One B-rep face of a CAD part: STEP entity #672.
In plain terms, the planar face has unit normal (0, -1, 0).
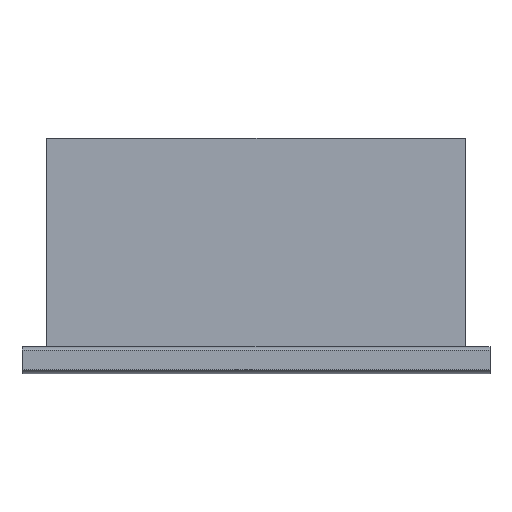
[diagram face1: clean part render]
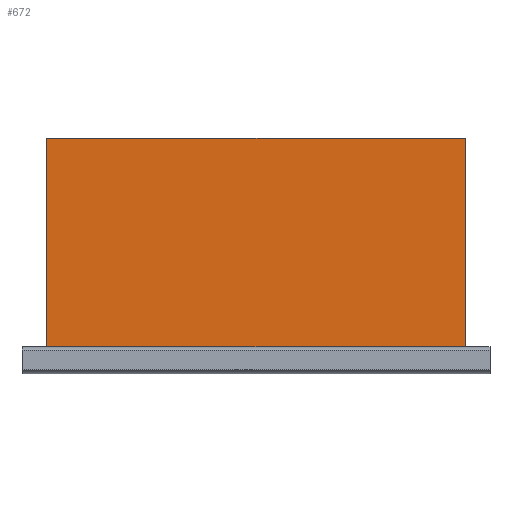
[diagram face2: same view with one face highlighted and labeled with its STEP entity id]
Its self-contained STEP definition (entity closure, numbers rounded to 3 decimals):
#117 = CYLINDRICAL_SURFACE('',#118,1.1);
#118 = AXIS2_PLACEMENT_3D('',#119,#120,#121);
#119 = CARTESIAN_POINT('',(-19.,0.,0.));
#120 = DIRECTION('',(1.,0.,0.));
#121 = DIRECTION('',(0.,0.,-1.));
#144 = PLANE('',#145);
#145 = AXIS2_PLACEMENT_3D('',#146,#147,#148);
#146 = CARTESIAN_POINT('',(-17.,-0.25,0.));
#147 = DIRECTION('',(1.,0.,0.));
#148 = DIRECTION('',(0.,0.,1.));
#172 = PLANE('',#173);
#173 = AXIS2_PLACEMENT_3D('',#174,#175,#176);
#174 = CARTESIAN_POINT('',(-17.,-0.25,18.));
#175 = DIRECTION('',(0.,0.,1.));
#176 = DIRECTION('',(1.,0.,-0.));
#200 = PLANE('',#201);
#201 = AXIS2_PLACEMENT_3D('',#202,#203,#204);
#202 = CARTESIAN_POINT('',(17.,-0.25,0.));
#203 = DIRECTION('',(1.,0.,0.));
#204 = DIRECTION('',(0.,0.,1.));
#397 = VERTEX_POINT('',#398);
#398 = CARTESIAN_POINT('',(17.,-0.25,1.071));
#420 = EDGE_CURVE('',#421,#397,#423,.T.);
#421 = VERTEX_POINT('',#422);
#422 = CARTESIAN_POINT('',(-17.,-0.25,1.071));
#423 = SURFACE_CURVE('',#424,(#428,#434),.PCURVE_S1.);
#424 = LINE('',#425,#426);
#425 = CARTESIAN_POINT('',(-19.,-0.25,1.071));
#426 = VECTOR('',#427,1.);
#427 = DIRECTION('',(1.,0.,0.));
#428 = PCURVE('',#117,#429);
#429 = DEFINITIONAL_REPRESENTATION('',(#430),#433);
#430 = B_SPLINE_CURVE_WITH_KNOTS('',1,(#431,#432),.UNSPECIFIED.,.F.,.F.,
  (2,2),(0.,38.),.PIECEWISE_BEZIER_KNOTS.);
#431 = CARTESIAN_POINT('',(3.371,0.));
#432 = CARTESIAN_POINT('',(3.371,38.));
#433 = ( GEOMETRIC_REPRESENTATION_CONTEXT(2) 
PARAMETRIC_REPRESENTATION_CONTEXT() REPRESENTATION_CONTEXT('2D SPACE',''
  ) );
#434 = PCURVE('',#435,#440);
#435 = PLANE('',#436);
#436 = AXIS2_PLACEMENT_3D('',#437,#438,#439);
#437 = CARTESIAN_POINT('',(-17.,-0.25,0.));
#438 = DIRECTION('',(0.,1.,0.));
#439 = DIRECTION('',(0.,-0.,1.));
#440 = DEFINITIONAL_REPRESENTATION('',(#441),#445);
#441 = LINE('',#442,#443);
#442 = CARTESIAN_POINT('',(1.071,-2.));
#443 = VECTOR('',#444,1.);
#444 = DIRECTION('',(0.,1.));
#445 = ( GEOMETRIC_REPRESENTATION_CONTEXT(2) 
PARAMETRIC_REPRESENTATION_CONTEXT() REPRESENTATION_CONTEXT('2D SPACE',''
  ) );
#544 = EDGE_CURVE('',#397,#545,#547,.T.);
#545 = VERTEX_POINT('',#546);
#546 = CARTESIAN_POINT('',(17.,-0.25,18.));
#547 = SURFACE_CURVE('',#548,(#552,#559),.PCURVE_S1.);
#548 = LINE('',#549,#550);
#549 = CARTESIAN_POINT('',(17.,-0.25,0.));
#550 = VECTOR('',#551,1.);
#551 = DIRECTION('',(0.,0.,1.));
#552 = PCURVE('',#200,#553);
#553 = DEFINITIONAL_REPRESENTATION('',(#554),#558);
#554 = LINE('',#555,#556);
#555 = CARTESIAN_POINT('',(0.,0.));
#556 = VECTOR('',#557,1.);
#557 = DIRECTION('',(1.,0.));
#558 = ( GEOMETRIC_REPRESENTATION_CONTEXT(2) 
PARAMETRIC_REPRESENTATION_CONTEXT() REPRESENTATION_CONTEXT('2D SPACE',''
  ) );
#559 = PCURVE('',#435,#560);
#560 = DEFINITIONAL_REPRESENTATION('',(#561),#565);
#561 = LINE('',#562,#563);
#562 = CARTESIAN_POINT('',(0.,34.));
#563 = VECTOR('',#564,1.);
#564 = DIRECTION('',(1.,0.));
#565 = ( GEOMETRIC_REPRESENTATION_CONTEXT(2) 
PARAMETRIC_REPRESENTATION_CONTEXT() REPRESENTATION_CONTEXT('2D SPACE',''
  ) );
#594 = VERTEX_POINT('',#595);
#595 = CARTESIAN_POINT('',(-17.,-0.25,18.));
#616 = EDGE_CURVE('',#594,#545,#617,.T.);
#617 = SURFACE_CURVE('',#618,(#622,#629),.PCURVE_S1.);
#618 = LINE('',#619,#620);
#619 = CARTESIAN_POINT('',(-17.,-0.25,18.));
#620 = VECTOR('',#621,1.);
#621 = DIRECTION('',(1.,0.,0.));
#622 = PCURVE('',#172,#623);
#623 = DEFINITIONAL_REPRESENTATION('',(#624),#628);
#624 = LINE('',#625,#626);
#625 = CARTESIAN_POINT('',(0.,0.));
#626 = VECTOR('',#627,1.);
#627 = DIRECTION('',(1.,0.));
#628 = ( GEOMETRIC_REPRESENTATION_CONTEXT(2) 
PARAMETRIC_REPRESENTATION_CONTEXT() REPRESENTATION_CONTEXT('2D SPACE',''
  ) );
#629 = PCURVE('',#435,#630);
#630 = DEFINITIONAL_REPRESENTATION('',(#631),#635);
#631 = LINE('',#632,#633);
#632 = CARTESIAN_POINT('',(18.,0.));
#633 = VECTOR('',#634,1.);
#634 = DIRECTION('',(0.,1.));
#635 = ( GEOMETRIC_REPRESENTATION_CONTEXT(2) 
PARAMETRIC_REPRESENTATION_CONTEXT() REPRESENTATION_CONTEXT('2D SPACE',''
  ) );
#642 = EDGE_CURVE('',#421,#594,#643,.T.);
#643 = SURFACE_CURVE('',#644,(#648,#655),.PCURVE_S1.);
#644 = LINE('',#645,#646);
#645 = CARTESIAN_POINT('',(-17.,-0.25,0.));
#646 = VECTOR('',#647,1.);
#647 = DIRECTION('',(0.,0.,1.));
#648 = PCURVE('',#144,#649);
#649 = DEFINITIONAL_REPRESENTATION('',(#650),#654);
#650 = LINE('',#651,#652);
#651 = CARTESIAN_POINT('',(0.,0.));
#652 = VECTOR('',#653,1.);
#653 = DIRECTION('',(1.,0.));
#654 = ( GEOMETRIC_REPRESENTATION_CONTEXT(2) 
PARAMETRIC_REPRESENTATION_CONTEXT() REPRESENTATION_CONTEXT('2D SPACE',''
  ) );
#655 = PCURVE('',#435,#656);
#656 = DEFINITIONAL_REPRESENTATION('',(#657),#661);
#657 = LINE('',#658,#659);
#658 = CARTESIAN_POINT('',(0.,0.));
#659 = VECTOR('',#660,1.);
#660 = DIRECTION('',(1.,0.));
#661 = ( GEOMETRIC_REPRESENTATION_CONTEXT(2) 
PARAMETRIC_REPRESENTATION_CONTEXT() REPRESENTATION_CONTEXT('2D SPACE',''
  ) );
#672 = ADVANCED_FACE('',(#673),#435,.F.);
#673 = FACE_BOUND('',#674,.F.);
#674 = EDGE_LOOP('',(#675,#676,#677,#678));
#675 = ORIENTED_EDGE('',*,*,#544,.F.);
#676 = ORIENTED_EDGE('',*,*,#420,.F.);
#677 = ORIENTED_EDGE('',*,*,#642,.T.);
#678 = ORIENTED_EDGE('',*,*,#616,.T.);
